VERSION 5.7 ;
  NOWIREEXTENSIONATPIN ON ;
  DIVIDERCHAR "/" ;
  BUSBITCHARS "[]" ;
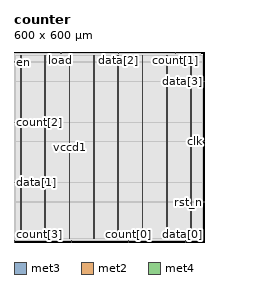
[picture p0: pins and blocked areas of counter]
MACRO counter
  CLASS BLOCK ;
  FOREIGN counter ;
  ORIGIN 0.000 0.000 ;
  SIZE 600.000 BY 600.000 ;
  PIN clk
    DIRECTION INPUT ;
    USE SIGNAL ;
    PORT
      LAYER met3 ;
        RECT 596.000 316.240 600.000 316.840 ;
    END
  END clk
  PIN count[0]
    DIRECTION OUTPUT TRISTATE ;
    USE SIGNAL ;
    PORT
      LAYER met2 ;
        RECT 360.730 0.000 361.010 4.000 ;
    END
  END count[0]
  PIN count[1]
    DIRECTION OUTPUT TRISTATE ;
    USE SIGNAL ;
    PORT
      LAYER met2 ;
        RECT 508.850 596.000 509.130 600.000 ;
    END
  END count[1]
  PIN count[2]
    DIRECTION OUTPUT TRISTATE ;
    USE SIGNAL ;
    PORT
      LAYER met3 ;
        RECT 0.000 377.440 4.000 378.040 ;
    END
  END count[2]
  PIN count[3]
    DIRECTION OUTPUT TRISTATE ;
    USE SIGNAL ;
    PORT
      LAYER met2 ;
        RECT 0.090 0.000 0.370 4.000 ;
    END
  END count[3]
  PIN data[0]
    DIRECTION INPUT ;
    USE SIGNAL ;
    PORT
      LAYER met2 ;
        RECT 541.050 0.000 541.330 4.000 ;
    END
  END data[0]
  PIN data[1]
    DIRECTION INPUT ;
    USE SIGNAL ;
    PORT
      LAYER met3 ;
        RECT 0.000 187.040 4.000 187.640 ;
    END
  END data[1]
  PIN data[2]
    DIRECTION INPUT ;
    USE SIGNAL ;
    PORT
      LAYER met2 ;
        RECT 328.530 596.000 328.810 600.000 ;
    END
  END data[2]
  PIN data[3]
    DIRECTION INPUT ;
    USE SIGNAL ;
    PORT
      LAYER met3 ;
        RECT 596.000 506.640 600.000 507.240 ;
    END
  END data[3]
  PIN dn
    DIRECTION INPUT ;
    USE SIGNAL ;
    PORT
      LAYER met2 ;
        RECT 180.410 0.000 180.690 4.000 ;
    END
  END dn
  PIN en
    DIRECTION INPUT ;
    USE SIGNAL ;
    PORT
      LAYER met3 ;
        RECT 0.000 567.840 4.000 568.440 ;
    END
  END en
  PIN load
    DIRECTION INPUT ;
    USE SIGNAL ;
    PORT
      LAYER met2 ;
        RECT 148.210 596.000 148.490 600.000 ;
    END
  END load
  PIN rst_n
    DIRECTION INPUT ;
    USE SIGNAL ;
    PORT
      LAYER met3 ;
        RECT 596.000 125.840 600.000 126.440 ;
    END
  END rst_n
  PIN vccd1
    DIRECTION INPUT ;
    USE POWER ;
    PORT
      LAYER met4 ;
        RECT 21.040 10.640 22.640 587.760 ;
    END
    PORT
      LAYER met4 ;
        RECT 174.640 10.640 176.240 587.760 ;
    END
    PORT
      LAYER met4 ;
        RECT 328.240 10.640 329.840 587.760 ;
    END
    PORT
      LAYER met4 ;
        RECT 481.840 10.640 483.440 587.760 ;
    END
  END vccd1
  PIN vssd1
    DIRECTION INPUT ;
    USE GROUND ;
    PORT
      LAYER met4 ;
        RECT 97.840 10.640 99.440 587.760 ;
    END
    PORT
      LAYER met4 ;
        RECT 251.440 10.640 253.040 587.760 ;
    END
    PORT
      LAYER met4 ;
        RECT 405.040 10.640 406.640 587.760 ;
    END
    PORT
      LAYER met4 ;
        RECT 558.640 10.640 560.240 587.760 ;
    END
  END vssd1
  OBS
      LAYER li1 ;
        RECT 5.520 10.795 595.095 587.605 ;
      LAYER met1 ;
        RECT 0.070 10.640 595.155 587.760 ;
      LAYER met2 ;
        RECT 0.100 595.720 147.930 596.000 ;
        RECT 148.770 595.720 328.250 596.000 ;
        RECT 329.090 595.720 508.570 596.000 ;
        RECT 509.410 595.720 588.710 596.000 ;
        RECT 0.100 4.280 588.710 595.720 ;
        RECT 0.650 4.000 180.130 4.280 ;
        RECT 180.970 4.000 360.450 4.280 ;
        RECT 361.290 4.000 540.770 4.280 ;
        RECT 541.610 4.000 588.710 4.280 ;
      LAYER met3 ;
        RECT 4.000 568.840 596.000 587.685 ;
        RECT 4.400 567.440 596.000 568.840 ;
        RECT 4.000 507.640 596.000 567.440 ;
        RECT 4.000 506.240 595.600 507.640 ;
        RECT 4.000 378.440 596.000 506.240 ;
        RECT 4.400 377.040 596.000 378.440 ;
        RECT 4.000 317.240 596.000 377.040 ;
        RECT 4.000 315.840 595.600 317.240 ;
        RECT 4.000 188.040 596.000 315.840 ;
        RECT 4.400 186.640 596.000 188.040 ;
        RECT 4.000 126.840 596.000 186.640 ;
        RECT 4.000 125.440 595.600 126.840 ;
        RECT 4.000 10.715 596.000 125.440 ;
  END
END counter
END LIBRARY

